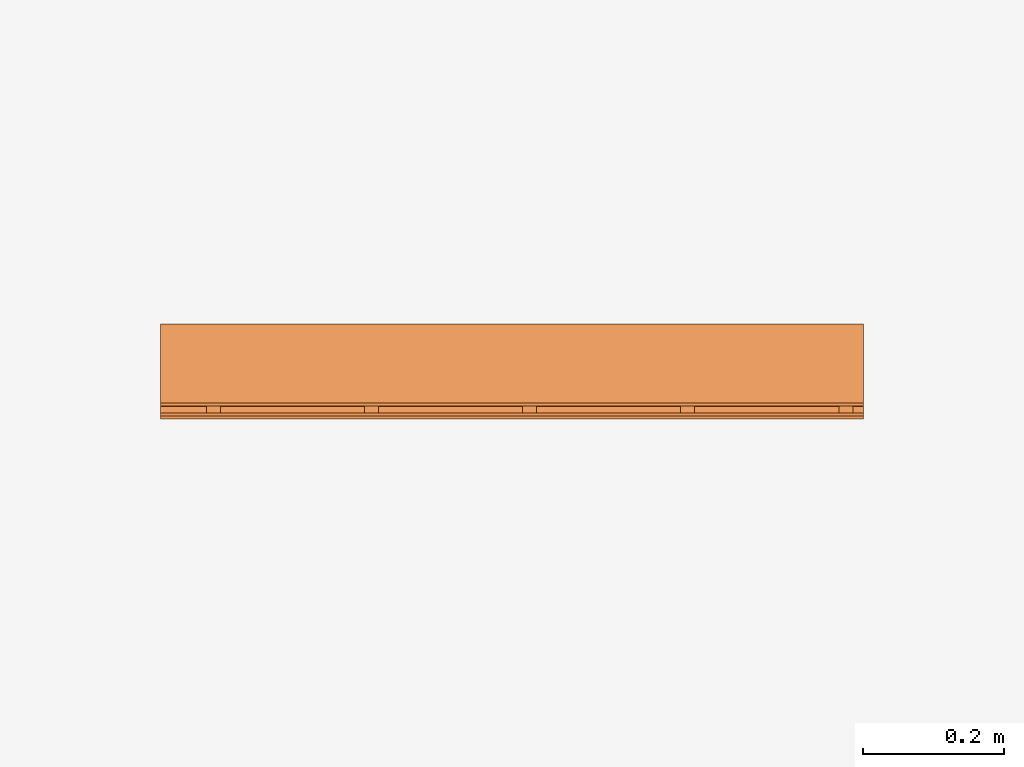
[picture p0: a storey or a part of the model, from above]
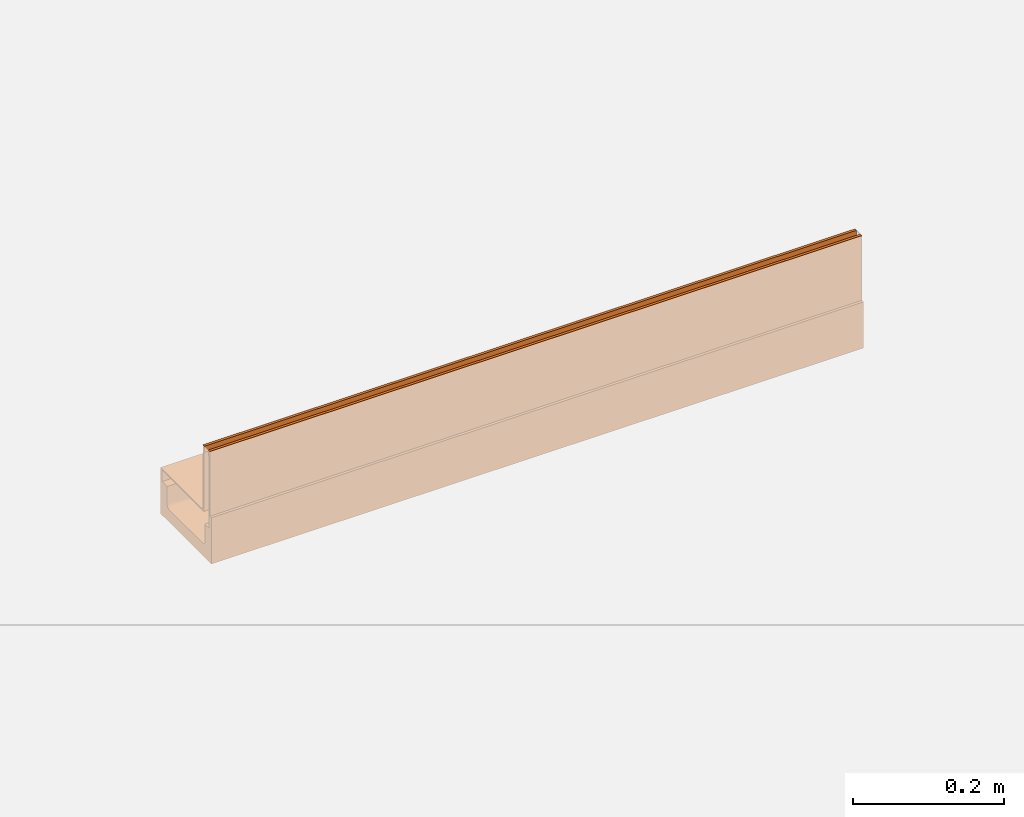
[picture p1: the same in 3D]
Properties of the parts of a building model (IFC2X3)

# File
Description: ViewDefinition [CoordinationView]
File name: 23075 - No 075 Constant Depth Shallow Channel - 1000mm LG - Invert Depth 55mm.ifc
Time: 2013-10-31T17:31:07
Written by: Autodesk Revit 2013
Made in: 20120221_2030(x64)

# IfcProject, Project Number
LongName: Project Name; Phase: Project Status

# IfcSite, Default
RefLatitude: 42, 21, 30, 344238; RefLongitude: -71, -3, -35, -194702; RefElevation: 0 mm

# IfcBuilding
Pset_BuildingCommon - NumberOfStoreys: 1
Other - Project Name: Project Name; Project Number: Project Number; Project Issue Date: Issue Date; Project Address: ## Street City, State Zip; Client Name: Owner; Project Status: Project Status

# IfcBuildingStorey, Level 1
LongName: Level 1; Elevation: 0 mm
Constraints - Elevation Base: 0; Elevation: 0 mm
Graphics - Symbol at End 1 Default: no; Line Weight: 1; Line Pattern: Center; Symbol at End 2 Default: yes; Symbol: M_Level Head - Circle: M_Level Head - Circle; Color: 0
Identity Data - Building Story: yes; Structural: no; Name: Level 1
Dimensions - Computation Height: 0 mm

# IfcBuildingElementProxy: 23075 - No 075 Constant Depth Shallow Channel - 1000mm LG - Invert Depth 55mm, Civil-Drainage-Channel-ACO-MultiDrain-M100D-Brickslot-Channel-System:23075 - No 075 Constant Depth Shallow Channel - 1000mm LG - Invert Depth 55mm:23075 - No 075 Constant Depth Shallow Channel - 1000mm LG - Invert Depth 55mm:196059
In: Level 1
Material: Steel, Galvanized, Vienite® Synthetic Resin Concrete
Construction - 23466_Load Class D400_Brickslot Grating_Galvanized Steel_500mm Long: no; 23460_Load Class C250_Brickslot Grating_Galvanized Steel_1000mm Long: no; 23404_Universal Endcap (Male End): no; 23404_Universal Endcap (Female End): no; 23465_Load Class D400_Brickslot Grating_Galvanized Steel_1000mm Long: yes; 23461_Load Class C250_Brickslot Grating_Galvanized Steel_500mm Long: no; 23462_Load Class C250_Brickslot Access Unit_Galvanised Steel_500mm Long: no; 23467_Load Class D400_Brickslot Access Unit_Galvanised Steel_500mm Long: no; Constant Depth Channel: no; Sloping Channel: no; Constant Depth Junction Channel: no; Shallow Depth Channel: yes; Shallow Depth Channel with seal: no; 23410_Sump Unit: no
Dimensions - Brickslot Void Depth: 0 mm; Custom_Void_length: 0 mm; FloorCut_Length: -1000 mm; Brickslot Access Unit Void Depth: -6500 mm; EndCap Position: 1000 mm; Brickslot Access Unit Void Bottom Depth: -6605 mm; Volume: 4900390 mm3; Length: 1000 mm; Brickslot Void Length: 1000 mm; GratingLength: -1000 mm; SlopingOverallDepth: 245 mm; EndCap_Height: 75 mm; Brickslot Access Unit Floor Cut Length: 500 mm; Floor Cut Gap: 105 mm; FloorCut_Depth: 75 mm; InvDepth: 80 mm; SlopingEndOverallDepth: 250 mm; SlopingEndInvertDepth: 180 mm; ShallowOverallDepth: 75 mm; Access_Custom_Void_Length: 0 mm; ShallowInvDepth: 55 mm; Depth: 150 mm; Length Drain: -1000 mm; FloorCut_Width: 135 mm; SlopingInvertDepth: 175 mm
Phasing - Phase Created: New Construction
Constraints - Level: Level: Level 1; Moves With Nearby Elements: no
Pset_BuildingElementProxyCommon - Reference: 23075 - No 075 Constant Depth Shallow Channel - 1000mm LG - Invert Depth 55mm
Other - Watermarked By: www.aco.co.uk; Created By: www.aco.co.uk; Revision: 1
Identity Data - Watermark 2: This file is water marked and users are prohibited to reproduce, adapt, distribute this information; Installation guidelines: http://www.aco.co.uk/download.php?id=173; Watermark 1: This file is the property of ACO Technologies PLC; Maintenance guidelines: http://www.aco.co.uk/download.php?id=173; Address: ACO Business Park, Hitchin Road, Shefford, Bedfordshire, United Kingdom SG17 5TE; Price: POA - contact ACO; Model Description: Channel drainage system; Assembly Code: D2040; Cost: 0; Model: ACO MultiDrain MD Brickslot- M100D; OmniClass Number: 23.70.50.24; Product Code: 23075; Manufacturer: ACO Technologies plc - ACO Water Management Division; Telephone: +44 (0)1462 816666; URL: www.aco.co.uk; Product brochure: http://www.aco.co.uk/download.php?id=173; Type Comments: ACO MultiDrain M100D No 075 Constant Depth Shallow Channel 1000mm Long; e-mail Sales: customersupport@aco.co.uk; Product Page URL: http://www.aco.co.uk/product_detail.php?id=58; Watermarked With: BIM Manager Premium Suite; OmniClass Title: Rainwater Removal; Assembly Description: Rain Water Drainage; Fax: +44 (0)1462 815895; e-mail Technical: technical@aco.co.uk
General - TagNumber: 0; SerialNumber: 0
Materials and Finishes - Edge Rail Finish: Pre-galvanised; Edge Rail Material: Steel; Channel Material: Vienite® Synthetic Resin Concrete; Channel Colour: Brown; Edge Rail Colour: Silver
Data - Pre-formed Outlet Ø: N/A; Hydraulic Performance: http://www.aco.co.uk/download.php?id=173; Installation - Concrete Grade: Refer to brochure; Load Class: A 15 - D400; Product Dimensions: 1000mm x 135mm x 75mm (LxWxH); Product Weight: 9.2 Kg; Product Standard: BS EN 1433:2002, CE marked; ACO Hydraulic Design Software: http://www.acodesign.co.uk; Invert Depth: 55mm; Channel C.S.A: 0.0034m²; Concrete Surround Volume - Load Class D 400 - Concrete Pavement: 0.14m³/m; Concrete Surround Volume - Load Class A 15 - Concrete Pavement: 0.05m³/m; Concrete Surround Volume - Load Class B 125 - C 250 - Concrete Pavement: 0.09m³/m
Model Properties - Brickslot Access Unit Product code 23467: Load Class D400 - Brickslot Access Unit Galvanised Steel - 500mm long x 105mm high - 10mm Slot - Intake area - 10000mm²/m - 6.4 Kg; Brickslot Grating Product code 23466: Load Class D400 - Brickslot Galvanised Steel - 500mm long x 105mm high - 10mm Slot - Intake area - 10000mm²/m - 3.3 Kg; Brickslot Access Unit Product code 23462: Load Class C250 - Brickslot Access Unit Galvanised Steel - 500mm long x 105mm high - 10mm Slot - Intake area - 10000mm²/m - 6.4 Kg; End Cap Product code 23404: No 306 Universal End Cap - 135mm wide x 300mm long - Spigot Ø110mm x 50mm long - Silver - Polypropylene - 0.16kg; Brickslot Grating Product code 23465: Load Class D400 - Brickslot Galvanised Steel - 1000mm long x 105mm high - 10mm Slot - Intake area - 10000mm²/m - 6.6 Kg; Brickslot Grating Product code 23461: Load Class C250 - Brickslot Galvanised Steel - 500mm long x 105mm high - 10mm Slot - Intake area - 10000mm²/m -3.3 Kg; Brickslot Grating Product code 23460: Load Class C250 - Brickslot Galvanised Steel - 1000mm long x 105mm high - 10mm Slot - Intake area - 10000mm²/m - 6.6 Kg
Green Building Properties - Edge Rail Recyclable: Fully recyclable; Channel Recycled Material Content: 20% minimum; Edge Rail Recycled Material Content: Between 40% - 90%; Channel Recyclable: Fully recyclable

# IfcOpeningElement: Recess (2)
In: Level 1
Dimensions - Volume: 24987985000 mm3; Perimeter: 20000 mm; Thickness: 1000 mm; Area: 25000000 mm2
Phasing - Phase Created: New Construction
Constraints - Related to Mass: no; Level: Level: Level 1; Room Bounding: yes; Height Offset From Level: 0 mm
Structural - Structural: no; Enable Analytical Model: no
Construction - Default Thickness: 1000 mm; Function: 0
Analytical Properties - Absorptance: 0.1; Heat Transfer Coefficient (U): 0.837; Thermal Resistance (R): 1.19474; Thermal mass: 1359800; Roughness: 1
Materials and Finishes - Structural Material: Earth
Graphics - Coarse Scale Fill Color: 0

# IfcSlab: Floor:Generic Floor - 1000mm, Floor:Generic Floor - 1000mm:193825
In: Level 1
PredefinedType: FLOOR; Material: Earth 1000 mm
Dimensions - Volume: 24987985000 mm3; Perimeter: 20000 mm; Thickness: 1000 mm; Area: 25000000 mm2
Phasing - Phase Created: New Construction
Constraints - Related to Mass: no; Level: Level: Level 1; Room Bounding: yes; Height Offset From Level: 0 mm
Structural - Structural: no; Enable Analytical Model: no
Pset_SlabCommon - Reference: Generic Floor - 1000mm; IsExternal: no; LoadBearing: yes
Construction - Default Thickness: 1000 mm; Function: 0
Analytical Properties - Absorptance: 0.1; Heat Transfer Coefficient (U): 0.837; Thermal Resistance (R): 1.19474; Thermal mass: 1359800; Roughness: 1
Materials and Finishes - Structural Material: Earth
Graphics - Coarse Scale Fill Color: 0
